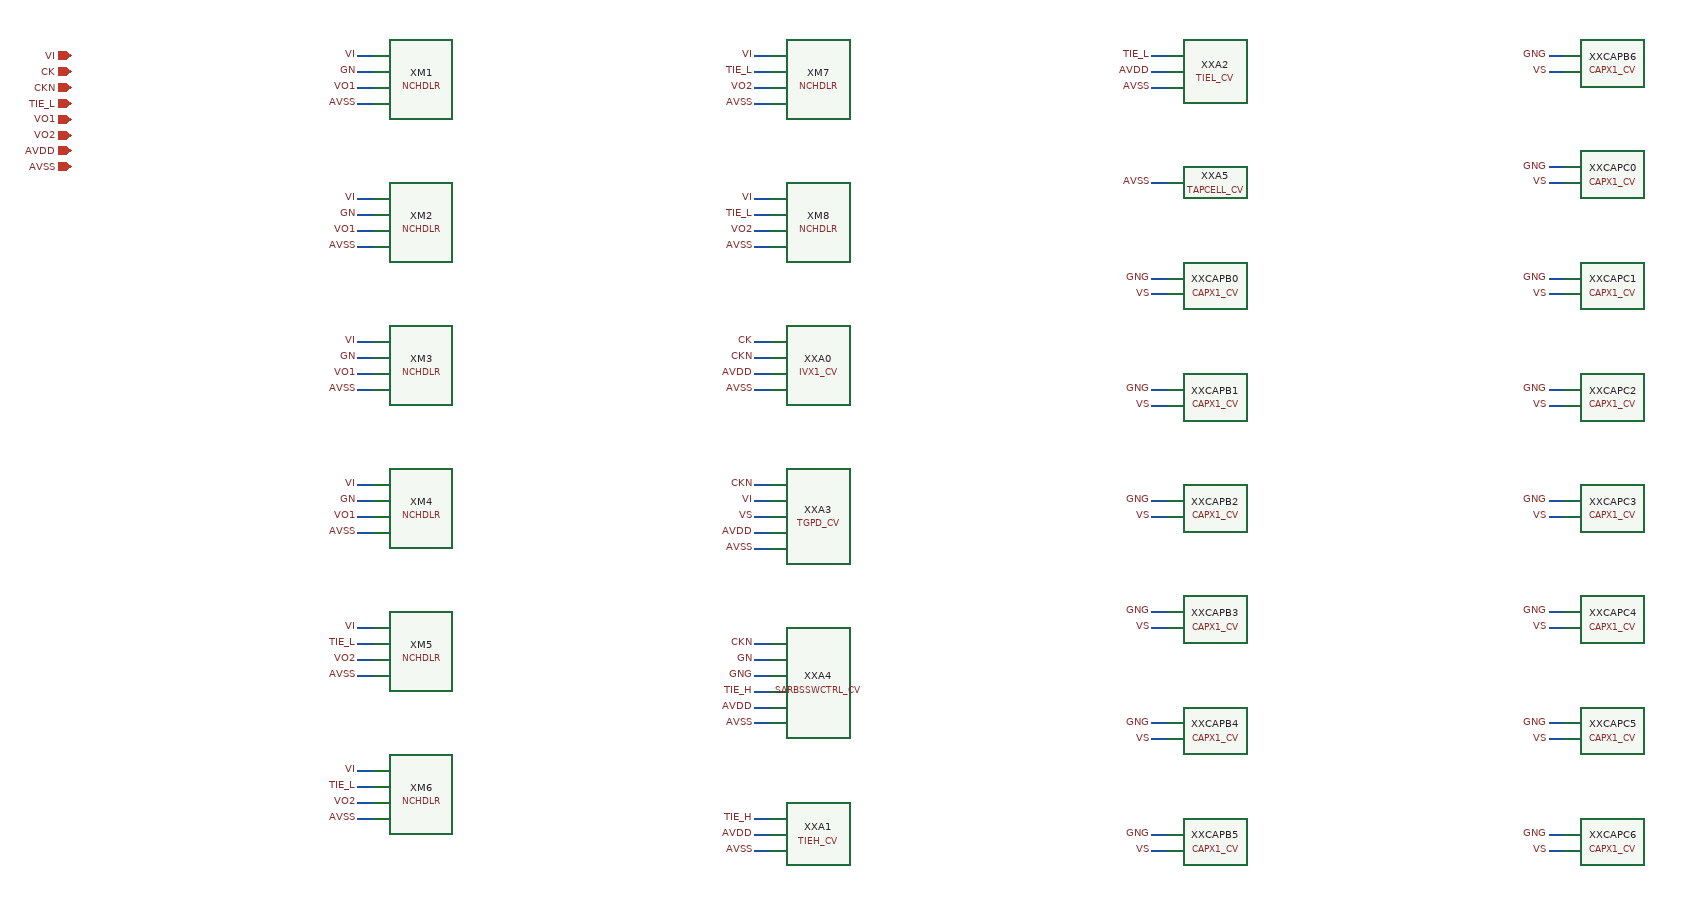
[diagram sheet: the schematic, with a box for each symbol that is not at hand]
v {xschem version=3.0.0 file_version=1.2 }
G {}
K {}
V {}
S {}
E {}
C {devices/iopin.sym} 0 0 0 0 {name=p0 lab=VI}
C {devices/iopin.sym} 0 20 0 0 {name=p1 lab=CK}
C {devices/iopin.sym} 0 40 0 0 {name=p2 lab=CKN}
C {devices/iopin.sym} 0 60 0 0 {name=p3 lab=TIE_L}
C {devices/iopin.sym} 0 80 0 0 {name=p4 lab=VO1}
C {devices/iopin.sym} 0 100 0 0 {name=p5 lab=VO2}
C {devices/iopin.sym} 0 120 0 0 {name=p6 lab=AVDD}
C {devices/iopin.sym} 0 140 0 0 {name=p7 lab=AVSS}
C {SAR9B/NCHDLR.sym} 400 0 0 0 {name=XM1}
N 360.0 0.0 380.0 0.0 {lab=VI}
C {devices/lab_pin.sym} 360.0 0.0 0 0 {name=l0 sig_type=std_logic lab=VI }
N 360.0 20.0 380.0 20.0 {lab=GN}
C {devices/lab_pin.sym} 360.0 20.0 0 0 {name=l1 sig_type=std_logic lab=GN }
N 360.0 40.0 380.0 40.0 {lab=VO1}
C {devices/lab_pin.sym} 360.0 40.0 0 0 {name=l2 sig_type=std_logic lab=VO1 }
N 360.0 60.0 380.0 60.0 {lab=AVSS}
C {devices/lab_pin.sym} 360.0 60.0 0 0 {name=l3 sig_type=std_logic lab=AVSS }
C {SAR9B/NCHDLR.sym} 400 180.0 0 0 {name=XM2}
N 360.0 180.0 380.0 180.0 {lab=VI}
C {devices/lab_pin.sym} 360.0 180.0 0 0 {name=l4 sig_type=std_logic lab=VI }
N 360.0 200.0 380.0 200.0 {lab=GN}
C {devices/lab_pin.sym} 360.0 200.0 0 0 {name=l5 sig_type=std_logic lab=GN }
N 360.0 220.0 380.0 220.0 {lab=VO1}
C {devices/lab_pin.sym} 360.0 220.0 0 0 {name=l6 sig_type=std_logic lab=VO1 }
N 360.0 240.0 380.0 240.0 {lab=AVSS}
C {devices/lab_pin.sym} 360.0 240.0 0 0 {name=l7 sig_type=std_logic lab=AVSS }
C {SAR9B/NCHDLR.sym} 400 360.0 0 0 {name=XM3}
N 360.0 360.0 380.0 360.0 {lab=VI}
C {devices/lab_pin.sym} 360.0 360.0 0 0 {name=l8 sig_type=std_logic lab=VI }
N 360.0 380.0 380.0 380.0 {lab=GN}
C {devices/lab_pin.sym} 360.0 380.0 0 0 {name=l9 sig_type=std_logic lab=GN }
N 360.0 400.0 380.0 400.0 {lab=VO1}
C {devices/lab_pin.sym} 360.0 400.0 0 0 {name=l10 sig_type=std_logic lab=VO1 }
N 360.0 420.0 380.0 420.0 {lab=AVSS}
C {devices/lab_pin.sym} 360.0 420.0 0 0 {name=l11 sig_type=std_logic lab=AVSS }
C {SAR9B/NCHDLR.sym} 400 540.0 0 0 {name=XM4}
N 360.0 540.0 380.0 540.0 {lab=VI}
C {devices/lab_pin.sym} 360.0 540.0 0 0 {name=l12 sig_type=std_logic lab=VI }
N 360.0 560.0 380.0 560.0 {lab=GN}
C {devices/lab_pin.sym} 360.0 560.0 0 0 {name=l13 sig_type=std_logic lab=GN }
N 360.0 580.0 380.0 580.0 {lab=VO1}
C {devices/lab_pin.sym} 360.0 580.0 0 0 {name=l14 sig_type=std_logic lab=VO1 }
N 360.0 600.0 380.0 600.0 {lab=AVSS}
C {devices/lab_pin.sym} 360.0 600.0 0 0 {name=l15 sig_type=std_logic lab=AVSS }
C {SAR9B/NCHDLR.sym} 400 720.0 0 0 {name=XM5}
N 360.0 720.0 380.0 720.0 {lab=VI}
C {devices/lab_pin.sym} 360.0 720.0 0 0 {name=l16 sig_type=std_logic lab=VI }
N 360.0 740.0 380.0 740.0 {lab=TIE_L}
C {devices/lab_pin.sym} 360.0 740.0 0 0 {name=l17 sig_type=std_logic lab=TIE_L }
N 360.0 760.0 380.0 760.0 {lab=VO2}
C {devices/lab_pin.sym} 360.0 760.0 0 0 {name=l18 sig_type=std_logic lab=VO2 }
N 360.0 780.0 380.0 780.0 {lab=AVSS}
C {devices/lab_pin.sym} 360.0 780.0 0 0 {name=l19 sig_type=std_logic lab=AVSS }
C {SAR9B/NCHDLR.sym} 400 900.0 0 0 {name=XM6}
N 360.0 900.0 380.0 900.0 {lab=VI}
C {devices/lab_pin.sym} 360.0 900.0 0 0 {name=l20 sig_type=std_logic lab=VI }
N 360.0 920.0 380.0 920.0 {lab=TIE_L}
C {devices/lab_pin.sym} 360.0 920.0 0 0 {name=l21 sig_type=std_logic lab=TIE_L }
N 360.0 940.0 380.0 940.0 {lab=VO2}
C {devices/lab_pin.sym} 360.0 940.0 0 0 {name=l22 sig_type=std_logic lab=VO2 }
N 360.0 960.0 380.0 960.0 {lab=AVSS}
C {devices/lab_pin.sym} 360.0 960.0 0 0 {name=l23 sig_type=std_logic lab=AVSS }
C {SAR9B/NCHDLR.sym} 900 0 0 0 {name=XM7}
N 860.0 0.0 880.0 0.0 {lab=VI}
C {devices/lab_pin.sym} 860.0 0.0 0 0 {name=l24 sig_type=std_logic lab=VI }
N 860.0 20.0 880.0 20.0 {lab=TIE_L}
C {devices/lab_pin.sym} 860.0 20.0 0 0 {name=l25 sig_type=std_logic lab=TIE_L }
N 860.0 40.0 880.0 40.0 {lab=VO2}
C {devices/lab_pin.sym} 860.0 40.0 0 0 {name=l26 sig_type=std_logic lab=VO2 }
N 860.0 60.0 880.0 60.0 {lab=AVSS}
C {devices/lab_pin.sym} 860.0 60.0 0 0 {name=l27 sig_type=std_logic lab=AVSS }
C {SAR9B/NCHDLR.sym} 900 180.0 0 0 {name=XM8}
N 860.0 180.0 880.0 180.0 {lab=VI}
C {devices/lab_pin.sym} 860.0 180.0 0 0 {name=l28 sig_type=std_logic lab=VI }
N 860.0 200.0 880.0 200.0 {lab=TIE_L}
C {devices/lab_pin.sym} 860.0 200.0 0 0 {name=l29 sig_type=std_logic lab=TIE_L }
N 860.0 220.0 880.0 220.0 {lab=VO2}
C {devices/lab_pin.sym} 860.0 220.0 0 0 {name=l30 sig_type=std_logic lab=VO2 }
N 860.0 240.0 880.0 240.0 {lab=AVSS}
C {devices/lab_pin.sym} 860.0 240.0 0 0 {name=l31 sig_type=std_logic lab=AVSS }
C {SAR9B/IVX1_CV.sym} 900 360.0 0 0 {name=XXA0}
N 860.0 360.0 880.0 360.0 {lab=CK}
C {devices/lab_pin.sym} 860.0 360.0 0 0 {name=l32 sig_type=std_logic lab=CK }
N 860.0 380.0 880.0 380.0 {lab=CKN}
C {devices/lab_pin.sym} 860.0 380.0 0 0 {name=l33 sig_type=std_logic lab=CKN }
N 860.0 400.0 880.0 400.0 {lab=AVDD}
C {devices/lab_pin.sym} 860.0 400.0 0 0 {name=l34 sig_type=std_logic lab=AVDD }
N 860.0 420.0 880.0 420.0 {lab=AVSS}
C {devices/lab_pin.sym} 860.0 420.0 0 0 {name=l35 sig_type=std_logic lab=AVSS }
C {SAR9B/TGPD_CV.sym} 900 540.0 0 0 {name=XXA3}
N 860.0 540.0 880.0 540.0 {lab=CKN}
C {devices/lab_pin.sym} 860.0 540.0 0 0 {name=l36 sig_type=std_logic lab=CKN }
N 860.0 560.0 880.0 560.0 {lab=VI}
C {devices/lab_pin.sym} 860.0 560.0 0 0 {name=l37 sig_type=std_logic lab=VI }
N 860.0 580.0 880.0 580.0 {lab=VS}
C {devices/lab_pin.sym} 860.0 580.0 0 0 {name=l38 sig_type=std_logic lab=VS }
N 860.0 600.0 880.0 600.0 {lab=AVDD}
C {devices/lab_pin.sym} 860.0 600.0 0 0 {name=l39 sig_type=std_logic lab=AVDD }
N 860.0 620.0 880.0 620.0 {lab=AVSS}
C {devices/lab_pin.sym} 860.0 620.0 0 0 {name=l40 sig_type=std_logic lab=AVSS }
C {SAR9B/SARBSSWCTRL_CV.sym} 900 740.0 0 0 {name=XXA4}
N 860.0 740.0 880.0 740.0 {lab=CKN}
C {devices/lab_pin.sym} 860.0 740.0 0 0 {name=l41 sig_type=std_logic lab=CKN }
N 860.0 760.0 880.0 760.0 {lab=GN}
C {devices/lab_pin.sym} 860.0 760.0 0 0 {name=l42 sig_type=std_logic lab=GN }
N 860.0 780.0 880.0 780.0 {lab=GNG}
C {devices/lab_pin.sym} 860.0 780.0 0 0 {name=l43 sig_type=std_logic lab=GNG }
N 860.0 800.0 880.0 800.0 {lab=TIE_H}
C {devices/lab_pin.sym} 860.0 800.0 0 0 {name=l44 sig_type=std_logic lab=TIE_H }
N 860.0 820.0 880.0 820.0 {lab=AVDD}
C {devices/lab_pin.sym} 860.0 820.0 0 0 {name=l45 sig_type=std_logic lab=AVDD }
N 860.0 840.0 880.0 840.0 {lab=AVSS}
C {devices/lab_pin.sym} 860.0 840.0 0 0 {name=l46 sig_type=std_logic lab=AVSS }
C {SAR9B/TIEH_CV.sym} 900 960.0 0 0 {name=XXA1}
N 860.0 960.0 880.0 960.0 {lab=TIE_H}
C {devices/lab_pin.sym} 860.0 960.0 0 0 {name=l47 sig_type=std_logic lab=TIE_H }
N 860.0 980.0 880.0 980.0 {lab=AVDD}
C {devices/lab_pin.sym} 860.0 980.0 0 0 {name=l48 sig_type=std_logic lab=AVDD }
N 860.0 1000.0 880.0 1000.0 {lab=AVSS}
C {devices/lab_pin.sym} 860.0 1000.0 0 0 {name=l49 sig_type=std_logic lab=AVSS }
C {SAR9B/TIEL_CV.sym} 1400 0 0 0 {name=XXA2}
N 1360.0 0.0 1380.0 0.0 {lab=TIE_L}
C {devices/lab_pin.sym} 1360.0 0.0 0 0 {name=l50 sig_type=std_logic lab=TIE_L }
N 1360.0 20.0 1380.0 20.0 {lab=AVDD}
C {devices/lab_pin.sym} 1360.0 20.0 0 0 {name=l51 sig_type=std_logic lab=AVDD }
N 1360.0 40.0 1380.0 40.0 {lab=AVSS}
C {devices/lab_pin.sym} 1360.0 40.0 0 0 {name=l52 sig_type=std_logic lab=AVSS }
C {SAR9B/TAPCELL_CV.sym} 1400 160.0 0 0 {name=XXA5}
N 1360.0 160.0 1380.0 160.0 {lab=AVSS}
C {devices/lab_pin.sym} 1360.0 160.0 0 0 {name=l53 sig_type=std_logic lab=AVSS }
C {SAR9B/CAPX1_CV.sym} 1400 280.0 0 0 {name=XXCAPB0}
N 1360.0 280.0 1380.0 280.0 {lab=GNG}
C {devices/lab_pin.sym} 1360.0 280.0 0 0 {name=l54 sig_type=std_logic lab=GNG }
N 1360.0 300.0 1380.0 300.0 {lab=VS}
C {devices/lab_pin.sym} 1360.0 300.0 0 0 {name=l55 sig_type=std_logic lab=VS }
C {SAR9B/CAPX1_CV.sym} 1400 420.0 0 0 {name=XXCAPB1}
N 1360.0 420.0 1380.0 420.0 {lab=GNG}
C {devices/lab_pin.sym} 1360.0 420.0 0 0 {name=l56 sig_type=std_logic lab=GNG }
N 1360.0 440.0 1380.0 440.0 {lab=VS}
C {devices/lab_pin.sym} 1360.0 440.0 0 0 {name=l57 sig_type=std_logic lab=VS }
C {SAR9B/CAPX1_CV.sym} 1400 560.0 0 0 {name=XXCAPB2}
N 1360.0 560.0 1380.0 560.0 {lab=GNG}
C {devices/lab_pin.sym} 1360.0 560.0 0 0 {name=l58 sig_type=std_logic lab=GNG }
N 1360.0 580.0 1380.0 580.0 {lab=VS}
C {devices/lab_pin.sym} 1360.0 580.0 0 0 {name=l59 sig_type=std_logic lab=VS }
C {SAR9B/CAPX1_CV.sym} 1400 700.0 0 0 {name=XXCAPB3}
N 1360.0 700.0 1380.0 700.0 {lab=GNG}
C {devices/lab_pin.sym} 1360.0 700.0 0 0 {name=l60 sig_type=std_logic lab=GNG }
N 1360.0 720.0 1380.0 720.0 {lab=VS}
C {devices/lab_pin.sym} 1360.0 720.0 0 0 {name=l61 sig_type=std_logic lab=VS }
C {SAR9B/CAPX1_CV.sym} 1400 840.0 0 0 {name=XXCAPB4}
N 1360.0 840.0 1380.0 840.0 {lab=GNG}
C {devices/lab_pin.sym} 1360.0 840.0 0 0 {name=l62 sig_type=std_logic lab=GNG }
N 1360.0 860.0 1380.0 860.0 {lab=VS}
C {devices/lab_pin.sym} 1360.0 860.0 0 0 {name=l63 sig_type=std_logic lab=VS }
C {SAR9B/CAPX1_CV.sym} 1400 980.0 0 0 {name=XXCAPB5}
N 1360.0 980.0 1380.0 980.0 {lab=GNG}
C {devices/lab_pin.sym} 1360.0 980.0 0 0 {name=l64 sig_type=std_logic lab=GNG }
N 1360.0 1000.0 1380.0 1000.0 {lab=VS}
C {devices/lab_pin.sym} 1360.0 1000.0 0 0 {name=l65 sig_type=std_logic lab=VS }
C {SAR9B/CAPX1_CV.sym} 1900 0 0 0 {name=XXCAPB6}
N 1860.0 0.0 1880.0 0.0 {lab=GNG}
C {devices/lab_pin.sym} 1860.0 0.0 0 0 {name=l66 sig_type=std_logic lab=GNG }
N 1860.0 20.0 1880.0 20.0 {lab=VS}
C {devices/lab_pin.sym} 1860.0 20.0 0 0 {name=l67 sig_type=std_logic lab=VS }
C {SAR9B/CAPX1_CV.sym} 1900 140.0 0 0 {name=XXCAPC0}
N 1860.0 140.0 1880.0 140.0 {lab=GNG}
C {devices/lab_pin.sym} 1860.0 140.0 0 0 {name=l68 sig_type=std_logic lab=GNG }
N 1860.0 160.0 1880.0 160.0 {lab=VS}
C {devices/lab_pin.sym} 1860.0 160.0 0 0 {name=l69 sig_type=std_logic lab=VS }
C {SAR9B/CAPX1_CV.sym} 1900 280.0 0 0 {name=XXCAPC1}
N 1860.0 280.0 1880.0 280.0 {lab=GNG}
C {devices/lab_pin.sym} 1860.0 280.0 0 0 {name=l70 sig_type=std_logic lab=GNG }
N 1860.0 300.0 1880.0 300.0 {lab=VS}
C {devices/lab_pin.sym} 1860.0 300.0 0 0 {name=l71 sig_type=std_logic lab=VS }
C {SAR9B/CAPX1_CV.sym} 1900 420.0 0 0 {name=XXCAPC2}
N 1860.0 420.0 1880.0 420.0 {lab=GNG}
C {devices/lab_pin.sym} 1860.0 420.0 0 0 {name=l72 sig_type=std_logic lab=GNG }
N 1860.0 440.0 1880.0 440.0 {lab=VS}
C {devices/lab_pin.sym} 1860.0 440.0 0 0 {name=l73 sig_type=std_logic lab=VS }
C {SAR9B/CAPX1_CV.sym} 1900 560.0 0 0 {name=XXCAPC3}
N 1860.0 560.0 1880.0 560.0 {lab=GNG}
C {devices/lab_pin.sym} 1860.0 560.0 0 0 {name=l74 sig_type=std_logic lab=GNG }
N 1860.0 580.0 1880.0 580.0 {lab=VS}
C {devices/lab_pin.sym} 1860.0 580.0 0 0 {name=l75 sig_type=std_logic lab=VS }
C {SAR9B/CAPX1_CV.sym} 1900 700.0 0 0 {name=XXCAPC4}
N 1860.0 700.0 1880.0 700.0 {lab=GNG}
C {devices/lab_pin.sym} 1860.0 700.0 0 0 {name=l76 sig_type=std_logic lab=GNG }
N 1860.0 720.0 1880.0 720.0 {lab=VS}
C {devices/lab_pin.sym} 1860.0 720.0 0 0 {name=l77 sig_type=std_logic lab=VS }
C {SAR9B/CAPX1_CV.sym} 1900 840.0 0 0 {name=XXCAPC5}
N 1860.0 840.0 1880.0 840.0 {lab=GNG}
C {devices/lab_pin.sym} 1860.0 840.0 0 0 {name=l78 sig_type=std_logic lab=GNG }
N 1860.0 860.0 1880.0 860.0 {lab=VS}
C {devices/lab_pin.sym} 1860.0 860.0 0 0 {name=l79 sig_type=std_logic lab=VS }
C {SAR9B/CAPX1_CV.sym} 1900 980.0 0 0 {name=XXCAPC6}
N 1860.0 980.0 1880.0 980.0 {lab=GNG}
C {devices/lab_pin.sym} 1860.0 980.0 0 0 {name=l80 sig_type=std_logic lab=GNG }
N 1860.0 1000.0 1880.0 1000.0 {lab=VS}
C {devices/lab_pin.sym} 1860.0 1000.0 0 0 {name=l81 sig_type=std_logic lab=VS }
